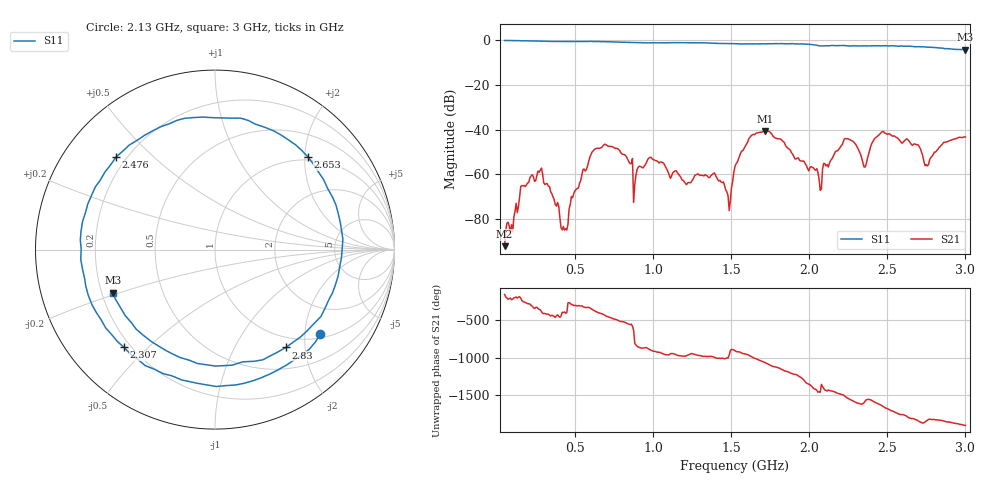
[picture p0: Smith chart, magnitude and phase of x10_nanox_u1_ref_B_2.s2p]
! nanovna_capture.py 2026-10-18T20:31:37+0900
! NanoVNA-F_V2 fw 0.6.0 SN 4A3639384505514B
! cal: load open short thru cal'ed  over 50000000-3000000000 Hz, 201 points
! points 401, avg 4
! S21: port1 = green ~10 mm H loop (flat, tape), port2 = GSM antenna; genuine Nano X u1 at position B, placement 2
# HZ S RI R 50
! S12 and S22 are not measured (written as 0)
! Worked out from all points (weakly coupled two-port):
!   401 points, 50 MHz to 3 GHz, reference 50 ohm
!   highest |S21| = -40.58 dB at 1.717 GHz (marker M1); lowest = -92.0 dB at 50 MHz (marker M2)
!   lowest |S11| = -4.2 dB at 3 GHz (marker M3), VSWR 4.21, Z = 12.3 - j9.55 ohm
!   |S11| at or under -10 dB: nowhere
!   S12 and S22 are empty: the file has one direction only
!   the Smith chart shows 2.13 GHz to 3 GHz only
!   S11 on the Smith chart (normalised r, x): 2.13 GHz: 1.11, -2.39; 2.307 GHz: 0.17, -0.42; 2.476 GHz: 0.16, +0.39; 2.653 GHz: 0.93, +2.07; 2.83 GHz: 0.82, -1.64; 3 GHz: 0.25, -0.19
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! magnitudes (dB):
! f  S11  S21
! 50 MHz  -0.1  -92.0
! 278.6 MHz  -0.4  -58.1
! 440.9 MHz  -0.6  -84.2
! 544.1 MHz  -0.6  -60.4
! 691.6 MHz  -0.6  -46.5
! 890.8 MHz  -1.0  -60.5
! 1.038 GHz  -1.2  -54.9
! 1.215 GHz  -1.1  -64.6
! 1.392 GHz  -1.4  -59.3
! 1.481 GHz  -1.5  -69.6
! 1.525 GHz  -1.6  -56.3
! 1.717 GHz  -1.6  -40.6
! 2.019 GHz  -1.9  -56.8
! 2.13 GHz  -2.5  -54.9
! 2.307 GHz  -2.6  -47.7
! 2.358 GHz  -2.5  -56.7
! 2.476 GHz  -2.4  -40.9
! 2.513 GHz  -2.5  -41.8
! 2.653 GHz  -2.7  -46.5
! 2.749 GHz  -3.1  -55.5
! 2.83 GHz  -3.4  -48.0
! 3 GHz  -4.2  -43.2
